VERSION 5.4 ;
NAMESCASESENSITIVE ON ;
BUSBITCHARS "[]" ;
DIVIDERCHAR "/" ;
UNITS
  DATABASE MICRONS 2000 ;
END UNITS
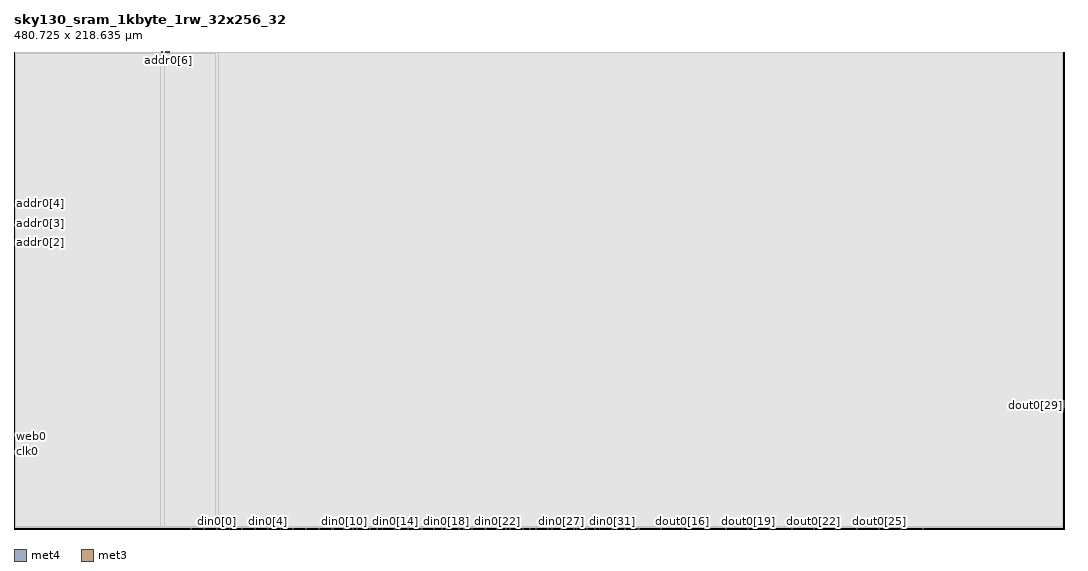
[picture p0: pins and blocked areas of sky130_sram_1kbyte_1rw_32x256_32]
MACRO sky130_sram_1kbyte_1rw_32x256_32
   CLASS BLOCK ;
   SIZE 480.725 BY 218.635 ;
   SYMMETRY X Y R90 ;
   PIN din0[0]
      DIRECTION INPUT ;
      PORT
         LAYER met4 ;
         RECT  92.64 0.0 93.02 0.38 ;
      END
   END din0[0]
   PIN din0[1]
      DIRECTION INPUT ;
      PORT
         LAYER met4 ;
         RECT  98.48 0.0 98.86 0.38 ;
      END
   END din0[1]
   PIN din0[2]
      DIRECTION INPUT ;
      PORT
         LAYER met4 ;
         RECT  104.32 0.0 104.7 0.38 ;
      END
   END din0[2]
   PIN din0[3]
      DIRECTION INPUT ;
      PORT
         LAYER met4 ;
         RECT  110.16 0.0 110.54 0.38 ;
      END
   END din0[3]
   PIN din0[4]
      DIRECTION INPUT ;
      PORT
         LAYER met4 ;
         RECT  116.0 0.0 116.38 0.38 ;
      END
   END din0[4]
   PIN din0[5]
      DIRECTION INPUT ;
      PORT
         LAYER met4 ;
         RECT  121.84 0.0 122.22 0.38 ;
      END
   END din0[5]
   PIN din0[6]
      DIRECTION INPUT ;
      PORT
         LAYER met4 ;
         RECT  127.68 0.0 128.06 0.38 ;
      END
   END din0[6]
   PIN din0[7]
      DIRECTION INPUT ;
      PORT
         LAYER met4 ;
         RECT  133.52 0.0 133.9 0.38 ;
      END
   END din0[7]
   PIN din0[8]
      DIRECTION INPUT ;
      PORT
         LAYER met4 ;
         RECT  139.36 0.0 139.74 0.38 ;
      END
   END din0[8]
   PIN din0[9]
      DIRECTION INPUT ;
      PORT
         LAYER met4 ;
         RECT  145.2 0.0 145.58 0.38 ;
      END
   END din0[9]
   PIN din0[10]
      DIRECTION INPUT ;
      PORT
         LAYER met4 ;
         RECT  151.04 0.0 151.42 0.38 ;
      END
   END din0[10]
   PIN din0[11]
      DIRECTION INPUT ;
      PORT
         LAYER met4 ;
         RECT  156.88 0.0 157.26 0.38 ;
      END
   END din0[11]
   PIN din0[12]
      DIRECTION INPUT ;
      PORT
         LAYER met4 ;
         RECT  162.72 0.0 163.1 0.38 ;
      END
   END din0[12]
   PIN din0[13]
      DIRECTION INPUT ;
      PORT
         LAYER met4 ;
         RECT  168.56 0.0 168.94 0.38 ;
      END
   END din0[13]
   PIN din0[14]
      DIRECTION INPUT ;
      PORT
         LAYER met4 ;
         RECT  174.4 0.0 174.78 0.38 ;
      END
   END din0[14]
   PIN din0[15]
      DIRECTION INPUT ;
      PORT
         LAYER met4 ;
         RECT  180.24 0.0 180.62 0.38 ;
      END
   END din0[15]
   PIN din0[16]
      DIRECTION INPUT ;
      PORT
         LAYER met4 ;
         RECT  186.08 0.0 186.46 0.38 ;
      END
   END din0[16]
   PIN din0[17]
      DIRECTION INPUT ;
      PORT
         LAYER met4 ;
         RECT  191.92 0.0 192.3 0.38 ;
      END
   END din0[17]
   PIN din0[18]
      DIRECTION INPUT ;
      PORT
         LAYER met4 ;
         RECT  197.76 0.0 198.14 0.38 ;
      END
   END din0[18]
   PIN din0[19]
      DIRECTION INPUT ;
      PORT
         LAYER met4 ;
         RECT  203.6 0.0 203.98 0.38 ;
      END
   END din0[19]
   PIN din0[20]
      DIRECTION INPUT ;
      PORT
         LAYER met4 ;
         RECT  209.44 0.0 209.82 0.38 ;
      END
   END din0[20]
   PIN din0[21]
      DIRECTION INPUT ;
      PORT
         LAYER met4 ;
         RECT  215.28 0.0 215.66 0.38 ;
      END
   END din0[21]
   PIN din0[22]
      DIRECTION INPUT ;
      PORT
         LAYER met4 ;
         RECT  221.12 0.0 221.5 0.38 ;
      END
   END din0[22]
   PIN din0[23]
      DIRECTION INPUT ;
      PORT
         LAYER met4 ;
         RECT  226.96 0.0 227.34 0.38 ;
      END
   END din0[23]
   PIN din0[24]
      DIRECTION INPUT ;
      PORT
         LAYER met4 ;
         RECT  232.8 0.0 233.18 0.38 ;
      END
   END din0[24]
   PIN din0[25]
      DIRECTION INPUT ;
      PORT
         LAYER met4 ;
         RECT  238.64 0.0 239.02 0.38 ;
      END
   END din0[25]
   PIN din0[26]
      DIRECTION INPUT ;
      PORT
         LAYER met4 ;
         RECT  244.48 0.0 244.86 0.38 ;
      END
   END din0[26]
   PIN din0[27]
      DIRECTION INPUT ;
      PORT
         LAYER met4 ;
         RECT  250.32 0.0 250.7 0.38 ;
      END
   END din0[27]
   PIN din0[28]
      DIRECTION INPUT ;
      PORT
         LAYER met4 ;
         RECT  256.16 0.0 256.54 0.38 ;
      END
   END din0[28]
   PIN din0[29]
      DIRECTION INPUT ;
      PORT
         LAYER met4 ;
         RECT  262.0 0.0 262.38 0.38 ;
      END
   END din0[29]
   PIN din0[30]
      DIRECTION INPUT ;
      PORT
         LAYER met4 ;
         RECT  267.84 0.0 268.22 0.38 ;
      END
   END din0[30]
   PIN din0[31]
      DIRECTION INPUT ;
      PORT
         LAYER met4 ;
         RECT  273.68 0.0 274.06 0.38 ;
      END
   END din0[31]
   PIN din0[32]
      DIRECTION INPUT ;
      PORT
         LAYER met4 ;
         RECT  279.52 0.0 279.9 0.38 ;
      END
   END din0[32]
   PIN addr0[0]
      DIRECTION INPUT ;
      PORT
         LAYER met4 ;
         RECT  80.96 0.0 81.34 0.38 ;
      END
   END addr0[0]
   PIN addr0[1]
      DIRECTION INPUT ;
      PORT
         LAYER met4 ;
         RECT  86.8 0.0 87.18 0.38 ;
      END
   END addr0[1]
   PIN addr0[2]
      DIRECTION INPUT ;
      PORT
         LAYER met3 ;
         RECT  0.0 131.025 0.38 131.405 ;
      END
   END addr0[2]
   PIN addr0[3]
      DIRECTION INPUT ;
      PORT
         LAYER met3 ;
         RECT  0.0 139.525 0.38 139.905 ;
      END
   END addr0[3]
   PIN addr0[4]
      DIRECTION INPUT ;
      PORT
         LAYER met3 ;
         RECT  0.0 145.165 0.38 145.545 ;
      END
   END addr0[4]
   PIN addr0[5]
      DIRECTION INPUT ;
      PORT
         LAYER met4 ;
         RECT  67.74 218.255 68.12 218.635 ;
      END
   END addr0[5]
   PIN addr0[6]
      DIRECTION INPUT ;
      PORT
         LAYER met4 ;
         RECT  70.715 218.255 71.095 218.635 ;
      END
   END addr0[6]
   PIN addr0[7]
      DIRECTION INPUT ;
      PORT
         LAYER met4 ;
         RECT  70.025 218.255 70.405 218.635 ;
      END
   END addr0[7]
   PIN addr0[8]
      DIRECTION INPUT ;
      PORT
         LAYER met4 ;
         RECT  69.28 218.255 69.66 218.635 ;
      END
   END addr0[8]
   PIN csb0
      DIRECTION INPUT ;
      PORT
         LAYER met3 ;
         RECT  0.0 33.985 0.38 34.365 ;
      END
   END csb0
   PIN web0
      DIRECTION INPUT ;
      PORT
         LAYER met3 ;
         RECT  0.0 42.385 0.38 42.765 ;
      END
   END web0
   PIN clk0
      DIRECTION INPUT ;
      PORT
         LAYER met3 ;
         RECT  0.0 35.475 0.38 35.855 ;
      END
   END clk0
   PIN spare_wen0
      DIRECTION INPUT ;
      PORT
         LAYER met4 ;
         RECT  285.36 0.0 285.74 0.38 ;
      END
   END spare_wen0
   PIN dout0[0]
      DIRECTION OUTPUT ;
      PORT
         LAYER met4 ;
         RECT  145.95 0.0 146.33 0.38 ;
      END
   END dout0[0]
   PIN dout0[1]
      DIRECTION OUTPUT ;
      PORT
         LAYER met4 ;
         RECT  155.075 0.0 155.455 0.38 ;
      END
   END dout0[1]
   PIN dout0[2]
      DIRECTION OUTPUT ;
      PORT
         LAYER met4 ;
         RECT  165.95 0.0 166.33 0.38 ;
      END
   END dout0[2]
   PIN dout0[3]
      DIRECTION OUTPUT ;
      PORT
         LAYER met4 ;
         RECT  175.95 0.0 176.33 0.38 ;
      END
   END dout0[3]
   PIN dout0[4]
      DIRECTION OUTPUT ;
      PORT
         LAYER met4 ;
         RECT  186.77 0.0 187.15 0.38 ;
      END
   END dout0[4]
   PIN dout0[5]
      DIRECTION OUTPUT ;
      PORT
         LAYER met4 ;
         RECT  195.95 0.0 196.33 0.38 ;
      END
   END dout0[5]
   PIN dout0[6]
      DIRECTION OUTPUT ;
      PORT
         LAYER met4 ;
         RECT  205.95 0.0 206.33 0.38 ;
      END
   END dout0[6]
   PIN dout0[7]
      DIRECTION OUTPUT ;
      PORT
         LAYER met4 ;
         RECT  216.01 0.0 216.39 0.38 ;
      END
   END dout0[7]
   PIN dout0[8]
      DIRECTION OUTPUT ;
      PORT
         LAYER met4 ;
         RECT  225.155 0.0 225.535 0.38 ;
      END
   END dout0[8]
   PIN dout0[9]
      DIRECTION OUTPUT ;
      PORT
         LAYER met4 ;
         RECT  235.95 0.0 236.33 0.38 ;
      END
   END dout0[9]
   PIN dout0[10]
      DIRECTION OUTPUT ;
      PORT
         LAYER met4 ;
         RECT  245.95 0.0 246.33 0.38 ;
      END
   END dout0[10]
   PIN dout0[11]
      DIRECTION OUTPUT ;
      PORT
         LAYER met4 ;
         RECT  257.33 0.0 257.71 0.38 ;
      END
   END dout0[11]
   PIN dout0[12]
      DIRECTION OUTPUT ;
      PORT
         LAYER met4 ;
         RECT  265.95 0.0 266.33 0.38 ;
      END
   END dout0[12]
   PIN dout0[13]
      DIRECTION OUTPUT ;
      PORT
         LAYER met4 ;
         RECT  275.95 0.0 276.33 0.38 ;
      END
   END dout0[13]
   PIN dout0[14]
      DIRECTION OUTPUT ;
      PORT
         LAYER met4 ;
         RECT  286.05 0.0 286.43 0.38 ;
      END
   END dout0[14]
   PIN dout0[15]
      DIRECTION OUTPUT ;
      PORT
         LAYER met4 ;
         RECT  295.95 0.0 296.33 0.38 ;
      END
   END dout0[15]
   PIN dout0[16]
      DIRECTION OUTPUT ;
      PORT
         LAYER met4 ;
         RECT  305.95 0.0 306.33 0.38 ;
      END
   END dout0[16]
   PIN dout0[17]
      DIRECTION OUTPUT ;
      PORT
         LAYER met4 ;
         RECT  315.95 0.0 316.33 0.38 ;
      END
   END dout0[17]
   PIN dout0[18]
      DIRECTION OUTPUT ;
      PORT
         LAYER met4 ;
         RECT  325.95 0.0 326.33 0.38 ;
      END
   END dout0[18]
   PIN dout0[19]
      DIRECTION OUTPUT ;
      PORT
         LAYER met4 ;
         RECT  335.95 0.0 336.33 0.38 ;
      END
   END dout0[19]
   PIN dout0[20]
      DIRECTION OUTPUT ;
      PORT
         LAYER met4 ;
         RECT  345.95 0.0 346.33 0.38 ;
      END
   END dout0[20]
   PIN dout0[21]
      DIRECTION OUTPUT ;
      PORT
         LAYER met4 ;
         RECT  355.95 0.0 356.33 0.38 ;
      END
   END dout0[21]
   PIN dout0[22]
      DIRECTION OUTPUT ;
      PORT
         LAYER met4 ;
         RECT  365.95 0.0 366.33 0.38 ;
      END
   END dout0[22]
   PIN dout0[23]
      DIRECTION OUTPUT ;
      PORT
         LAYER met4 ;
         RECT  375.95 0.0 376.33 0.38 ;
      END
   END dout0[23]
   PIN dout0[24]
      DIRECTION OUTPUT ;
      PORT
         LAYER met4 ;
         RECT  385.95 0.0 386.33 0.38 ;
      END
   END dout0[24]
   PIN dout0[25]
      DIRECTION OUTPUT ;
      PORT
         LAYER met4 ;
         RECT  395.95 0.0 396.33 0.38 ;
      END
   END dout0[25]
   PIN dout0[26]
      DIRECTION OUTPUT ;
      PORT
         LAYER met4 ;
         RECT  405.95 0.0 406.33 0.38 ;
      END
   END dout0[26]
   PIN dout0[27]
      DIRECTION OUTPUT ;
      PORT
         LAYER met4 ;
         RECT  415.95 0.0 416.33 0.38 ;
      END
   END dout0[27]
   PIN dout0[28]
      DIRECTION OUTPUT ;
      PORT
         LAYER met3 ;
         RECT  480.345 55.525 480.725 55.905 ;
      END
   END dout0[28]
   PIN dout0[29]
      DIRECTION OUTPUT ;
      PORT
         LAYER met3 ;
         RECT  480.345 56.215 480.725 56.595 ;
      END
   END dout0[29]
   PIN dout0[30]
      DIRECTION OUTPUT ;
      PORT
         LAYER met3 ;
         RECT  480.345 58.395 480.725 58.775 ;
      END
   END dout0[30]
   PIN dout0[31]
      DIRECTION OUTPUT ;
      PORT
         LAYER met3 ;
         RECT  480.345 56.905 480.725 57.285 ;
      END
   END dout0[31]
   PIN dout0[32]
      DIRECTION OUTPUT ;
      PORT
         LAYER met3 ;
         RECT  480.345 57.65 480.725 58.03 ;
      END
   END dout0[32]
   PIN vccd1
      DIRECTION INOUT ;
      USE POWER ; 
      SHAPE ABUTMENT ; 
      PORT
      END
   END vccd1
   PIN vssd1
      DIRECTION INOUT ;
      USE GROUND ; 
      SHAPE ABUTMENT ; 
      PORT
      END
   END vssd1
   OBS
   LAYER  met1 ;
      RECT  0.62 0.62 480.105 218.015 ;
   LAYER  met2 ;
      RECT  0.62 0.62 480.105 218.015 ;
   LAYER  met3 ;
      RECT  0.98 130.425 480.105 132.005 ;
      RECT  0.98 132.005 480.105 218.015 ;
      RECT  0.62 132.005 0.98 138.925 ;
      RECT  0.62 140.505 0.98 144.565 ;
      RECT  0.62 146.145 0.98 218.015 ;
      RECT  0.62 0.62 0.98 33.385 ;
      RECT  0.62 43.365 0.98 130.425 ;
      RECT  0.62 36.455 0.98 41.785 ;
      RECT  0.98 0.62 479.745 54.925 ;
      RECT  0.98 54.925 479.745 56.505 ;
      RECT  0.98 56.505 479.745 130.425 ;
      RECT  479.745 0.62 480.105 54.925 ;
      RECT  479.745 59.375 480.105 130.425 ;
   LAYER  met4 ;
      RECT  92.04 0.98 93.62 218.015 ;
      RECT  93.62 0.98 480.105 218.015 ;
      RECT  93.62 0.62 97.88 0.98 ;
      RECT  99.46 0.62 103.72 0.98 ;
      RECT  105.3 0.62 109.56 0.98 ;
      RECT  111.14 0.62 115.4 0.98 ;
      RECT  116.98 0.62 121.24 0.98 ;
      RECT  122.82 0.62 127.08 0.98 ;
      RECT  128.66 0.62 132.92 0.98 ;
      RECT  134.5 0.62 138.76 0.98 ;
      RECT  140.34 0.62 144.6 0.98 ;
      RECT  157.86 0.62 162.12 0.98 ;
      RECT  169.54 0.62 173.8 0.98 ;
      RECT  181.22 0.62 185.48 0.98 ;
      RECT  198.74 0.62 203.0 0.98 ;
      RECT  210.42 0.62 214.68 0.98 ;
      RECT  227.94 0.62 232.2 0.98 ;
      RECT  239.62 0.62 243.88 0.98 ;
      RECT  251.3 0.62 255.56 0.98 ;
      RECT  268.82 0.62 273.08 0.98 ;
      RECT  0.62 0.62 80.36 0.98 ;
      RECT  81.94 0.62 86.2 0.98 ;
      RECT  87.78 0.62 92.04 0.98 ;
      RECT  0.62 0.98 67.14 217.655 ;
      RECT  0.62 217.655 67.14 218.015 ;
      RECT  67.14 0.98 68.72 217.655 ;
      RECT  68.72 0.98 92.04 217.655 ;
      RECT  71.695 217.655 92.04 218.015 ;
      RECT  280.5 0.62 284.76 0.98 ;
      RECT  146.93 0.62 150.44 0.98 ;
      RECT  152.02 0.62 154.475 0.98 ;
      RECT  156.055 0.62 156.28 0.98 ;
      RECT  163.7 0.62 165.35 0.98 ;
      RECT  166.93 0.62 167.96 0.98 ;
      RECT  176.93 0.62 179.64 0.98 ;
      RECT  187.75 0.62 191.32 0.98 ;
      RECT  192.9 0.62 195.35 0.98 ;
      RECT  196.93 0.62 197.16 0.98 ;
      RECT  204.58 0.62 205.35 0.98 ;
      RECT  206.93 0.62 208.84 0.98 ;
      RECT  216.99 0.62 220.52 0.98 ;
      RECT  222.1 0.62 224.555 0.98 ;
      RECT  226.135 0.62 226.36 0.98 ;
      RECT  233.78 0.62 235.35 0.98 ;
      RECT  236.93 0.62 238.04 0.98 ;
      RECT  246.93 0.62 249.72 0.98 ;
      RECT  258.31 0.62 261.4 0.98 ;
      RECT  262.98 0.62 265.35 0.98 ;
      RECT  266.93 0.62 267.24 0.98 ;
      RECT  274.66 0.62 275.35 0.98 ;
      RECT  276.93 0.62 278.92 0.98 ;
      RECT  287.03 0.62 295.35 0.98 ;
      RECT  296.93 0.62 305.35 0.98 ;
      RECT  306.93 0.62 315.35 0.98 ;
      RECT  316.93 0.62 325.35 0.98 ;
      RECT  326.93 0.62 335.35 0.98 ;
      RECT  336.93 0.62 345.35 0.98 ;
      RECT  346.93 0.62 355.35 0.98 ;
      RECT  356.93 0.62 365.35 0.98 ;
      RECT  366.93 0.62 375.35 0.98 ;
      RECT  376.93 0.62 385.35 0.98 ;
      RECT  386.93 0.62 395.35 0.98 ;
      RECT  396.93 0.62 405.35 0.98 ;
      RECT  406.93 0.62 415.35 0.98 ;
      RECT  416.93 0.62 480.105 0.98 ;
   END
END    sky130_sram_1kbyte_1rw_32x256_32
END    LIBRARY
